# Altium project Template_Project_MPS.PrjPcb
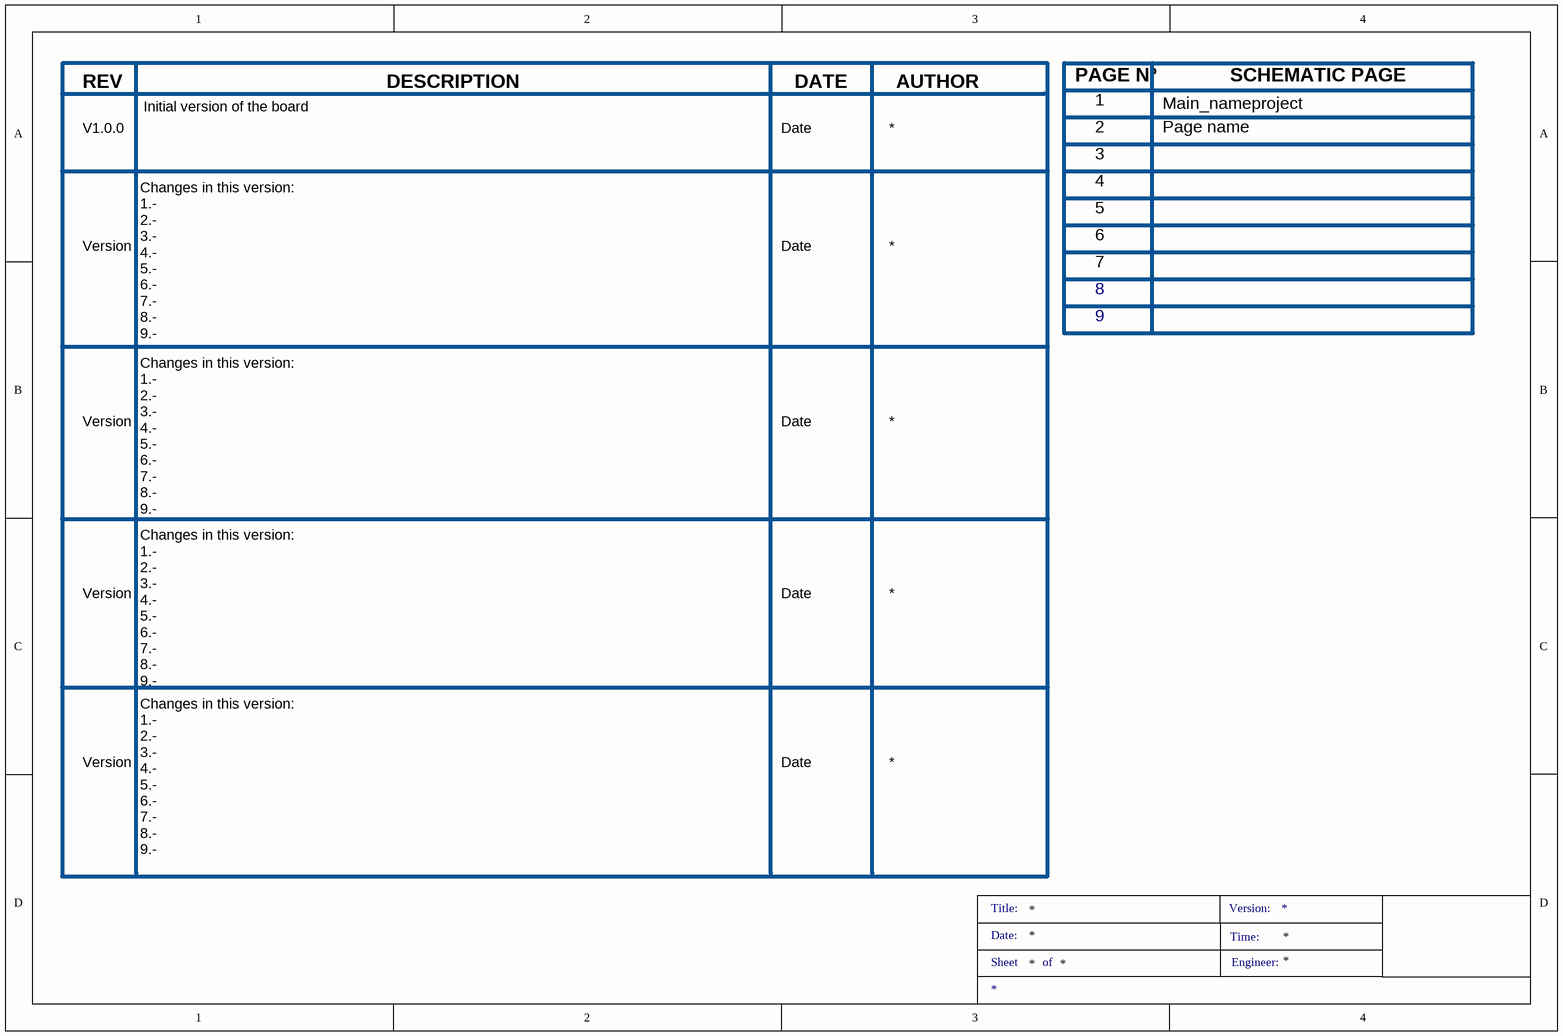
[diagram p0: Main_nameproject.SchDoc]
2 sheets, 0 parts. Net scope: global (net labels, ports and power ports of the same name join across sheets).
Sheets:
  Main_nameproject.SchDoc
  PowerSupplies.SchDoc

## Sheet Main_nameproject.SchDoc
size A4

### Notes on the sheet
- REV
- DESCRIPTION
- DATE
- AUTHOR
- PAGE Nº
- 1
- Main_nameproject
- SCHEMATIC PAGE
- V1.0.0
- Initial version of the board
- Date
- 2
- 3
- Page name
- 4
- 5
- 6
- Version
- 7
- 8
- Changes in this version:
  1.-
  2.-
  3.-
  4.-
  5.-
  6.-
  7.-
  8.-
  9.-
- 9

## Sheet PowerSupplies.SchDoc
size A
